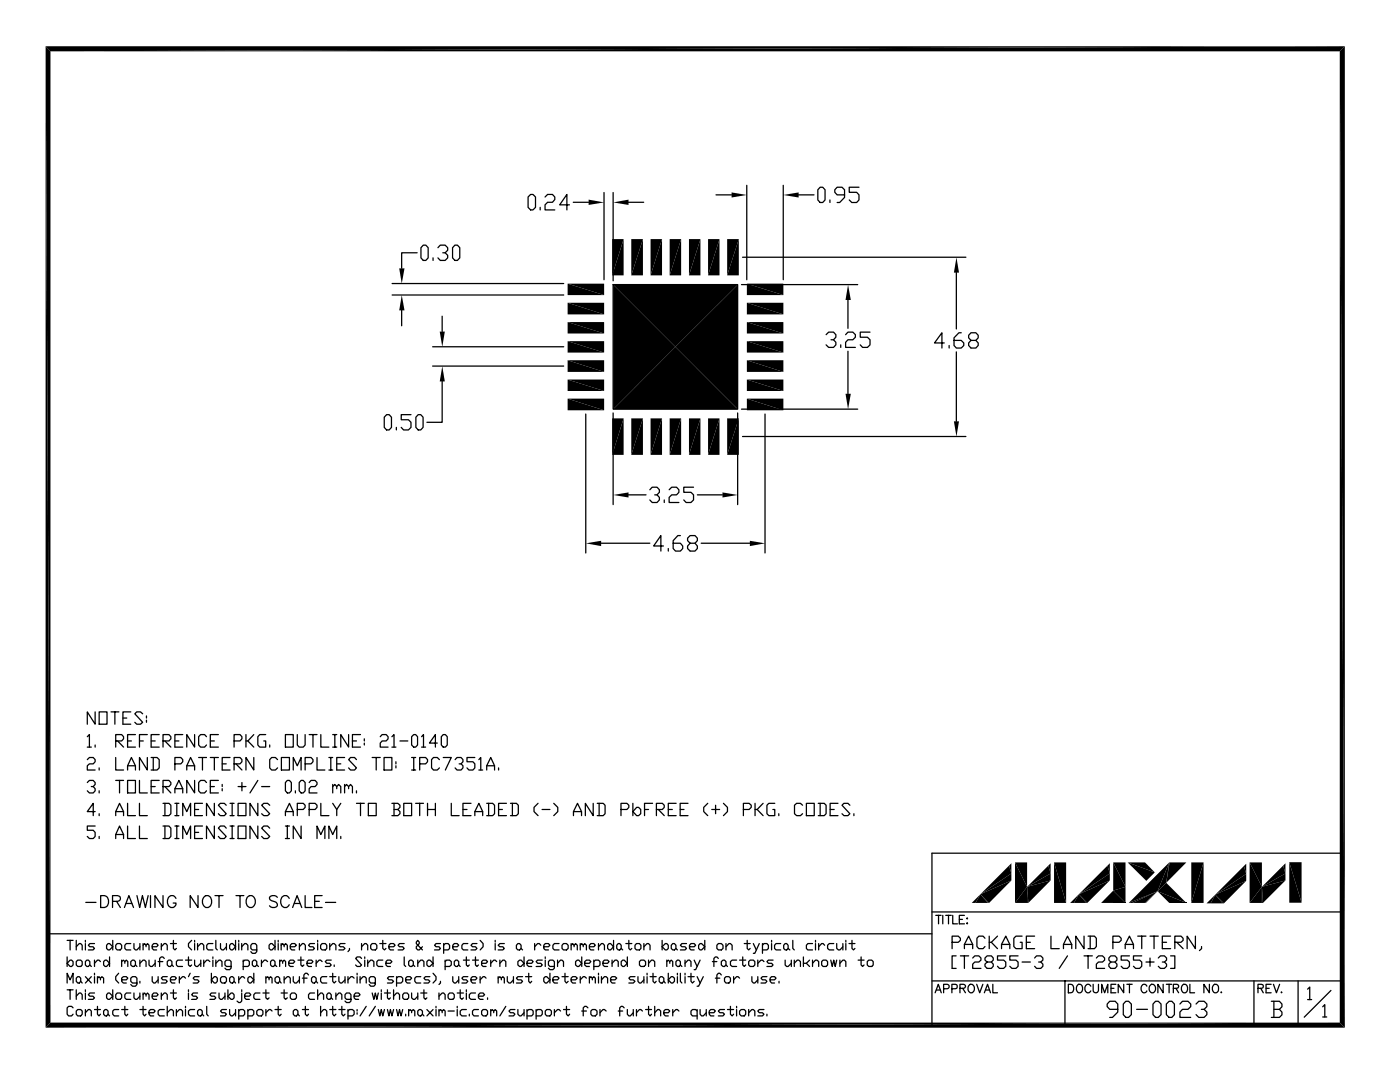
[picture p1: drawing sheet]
<svg xmlns="http://www.w3.org/2000/svg" width="279mm" height="216mm" viewBox="0 0 279 216" stroke-linecap="round" stroke-linejoin="round" font-family="sans-serif">
<g fill="none" stroke="#000" stroke-width=".25">
<path d="M105.4 39.3l.5-.5h.5l.5 .5v2.1l-.5 .5h-.5l-.5-.5zM108.8 39.3l.5-.5h1l.4 .5v.5l-.4 .6h-1l-.5 .5v1h1.9M120.5 38.4v17.4M122.4 38.4v17.6M142.9 38.9h3.1M149 37v18.8M156.3 37v18.8M159.4 38.9h3.1M163.7 37.4h.5l.5 .5v2l-.5 .5h-.5l-.5-.5v-2zM165.6 39.9v.5M168.6 38.9h-1.5l-.5-.5v-.5l.5-.5h.9l.6 .5v1.5l-1 1h-.5M171.4 37.4h-1.9v1h1.5l.4 .5v1l-.4 .5h-1l-.5-.5"/>
<path d="M78.3 56.6h34.2M78.3 58.9h34.2M83.2 50.4h-3v3.1M84.5 48.9h.5l.4 .5v2.1l-.4 .5h-.5l-.5-.5v-2.1zM86.4 51.5v.5M87.4 49.4l.5-.5h.9l.5 .5v.5l-.5 .5h-.4M88.8 50.4l.5 .5v.6l-.5 .5h-.9l-.5-.5M90.8 48.9h.5l.5 .5v2.1l-.5 .5h-.5l-.5-.5v-2.1zM107.8 41.4v.5M113.6 40.9h-1.9l1.4-2.1v3.1M114.4 40.4h3.1M122.4 56.8h24.8v24.8h-24.8z"/>
<path d="M125.4 40.4h3.1M148 56.8h23.2M148.2 51.3h44.6M169.2 59.8v5.7M190.9 54.4v11.2M80.2 61.9v3.1M86.3 73h26.2M86.3 69.2h26.2M88.2 76.1v8.2h-3M88.2 63.1v3M164.9 66.8l.5-.5h.9l.5 .5v.5l-.5 .5h-.5M166.3 67.8l.5 .5v.5l-.5 .5h-.9l-.5-.5"/>
<path d="M167.8 68.8v.5M168.8 66.8l.4-.5h1l.5 .5v.5l-.5 .5h-1l-.4 .5v1h1.9M169.2 70.1v8.4M173.6 66.3h-1.9v1h1.4l.5 .5v1l-.5 .5h-1l-.4-.5M188.4 68.4h-1.9l1.5-2v3M189.4 68.9v.5M190.9 70.2v13.9M191.8 66.4h-.4l-1 1v1.5l.5 .5h.9l.5-.5v-.5l-.5-.5h-1.4M193.8 67.9l-.5-.5v-.5l.5-.5h1l.4 .5v.5l-.4 .5h-1l-.5 .5v.5l.5 .5h1l.4-.5v-.5l-.4-.5M77.2 82.7h.5l.4 .5v2.1l-.4 .5h-.5l-.5-.5v-2.1zM79.1 85.3v.5M82 82.7h-1.9v1.1h1.4l.5 .5v1l-.5 .5h-1l-.4-.5"/>
<path d="M83.5 82.7h.5l.4 .5v2.1l-.4 .5h-.5l-.5-.5v-2.1zM116.9 82.6v27.7M122.4 82.4v18.3M125.4 98.7h3.5M129.7 97.7l.5-.5h.9l.5 .5v.5l-.5 .5h-.4M131.1 98.7l.5 .6v.5l-.5 .5h-.9l-.5-.5M132.6 99.8v.5M133.5 97.7l.5-.5h1l.5 .5v.5l-.5 .5h-1l-.5 .6v1h2M138.4 97.2h-1.9v1h1.4l.5 .5v1.1l-.5 .5h-1l-.4-.5M139.2 98.7h5M147.2 82.4v18.3M148 81.6h23.2"/>
<path d="M148.2 87.1h44.6M152.7 82.6v27.7M120 108.4h9.7M132.4 108.9h-1.9l1.4-2v3.1M133.4 109.5v.5M135.8 106.9h-.5l-1 1v1.6l.5 .5h1l.4-.5v-.6l-.4-.5h-1.5M137.7 108.4l-.5-.5v-.5l.5-.5h1l.5 .5v.5l-.5 .5h-1l-.5 .5v.6l.5 .5h1l.5-.5v-.6l-.5-.5M139.9 108.4h9.7M17.4 147l.4-.4v2.5M17.4 151.6l.4-.4h.8l.4 .4v.4l-.4 .4h-.8l-.4 .4v.8h1.6M17.4 156.1l.4-.4h.8l.4 .4v.4l-.4 .5h-.4M17.4 149.1h.8"/>
<path d="M18.6 157l.4 .4v.4l-.4 .4h-.8l-.4-.4M19 142v2.5l-1.6-2.5v2.5M19 148.7v.4M19.8 142h1.6v2.5h-1.6zM19.8 153.2v.4M19.8 157.8v.4M22.2 142h1.5M22.9 142v2.5M23.1 147.8h1.2l.4-.4v-.4l-.4-.4h-1.2v2.5M23.1 151.2v2.4h1.6M23.1 155.7h1.6M23.5 147.8l1.2 1.3"/>
<path d="M23.9 155.7v2.5M24.5 143.3h.8M25.5 153.6v-.8l.7-1.6 .8 1.6v.8M25.5 155.7h1.5v2.5h-1.5zM25.5 147.8h.7M25.5 152.8h1.5M26.1 142h-1.6v2.5h1.6M27 146.6h-1.5v2.5h1.5M27.8 155.7v2.5h1.6M27.8 147.8h.8M28.5 142.4l-.5-.4h-.7l-.4 .4 1.6 1.7-.5 .4h-.7l-.4-.4M29.2 142.9v.4"/>
<path d="M29.2 143.7v.4M29.4 146.6h-1.6v2.5M29.4 151.2v2.4l-1.6-2.4v2.4M30.2 151.2h1.1l.5 .4v1.6l-.5 .4h-1.1M30.2 147.8h.8M30.2 157h.8M30.6 151.2v2.4M31.8 146.6h-1.6v2.5h1.6M31.8 155.7h-1.6v2.5h1.6M32.5 147.8h1.2l.4-.4v-.4l-.4-.4h-1.2v2.5M32.5 157h1.2l.4-.5v-.4l-.4-.4h-1.2v2.5M32.9 147.8l1.2 1.3"/>
<path d="M32.9 157l1.2 1.2M34.9 152.4h1.2l.4-.4v-.4l-.4-.4h-1.2v2.4M34.9 158.2v-.8l.8-1.7 .8 1.7v.8M34.9 147.8h.8M34.9 157.4h1.6M36.5 146.6h-1.6v2.5h1.6M37.3 153.6v-.8l.7-1.6 .8 1.6v.8M37.3 152.8h1.5M38.8 146.6v2.5l-1.5-2.5v2.5M38.8 155.7v2.5l-1.5-2.5v2.5M39.6 151.2h1.6M40.4 151.2v2.4"/>
<path d="M41.2 147l-.4-.4h-.8l-.4 .4v1.7l.4 .4h.8l.4-.4M41.2 156.1l-.4-.4h-.8l-.4 .4v1.7l.4 .4h.8l.4-.4M42 147.8h.8M42 151.2h1.6M42 157h.8M42.8 151.2v2.4M43.6 146.6h-1.6v2.5h1.6M43.6 155.7h-1.6v2.5h1.6M44.3 152.4h.8M44.3 156.5v.5M44.3 157.4v.4M45.9 151.2h-1.6v2.4h1.6"/>
<path d="M46.7 147.8h1.2l.4-.4v-.4l-.4-.4h-1.2v2.5M46.7 152.4h1.2l.4-.4v-.4l-.4-.4h-1.2v2.4M47.1 152.4l1.2 1.2M47.5 157h1.6M48.3 156.1v1.7M49.1 146.6v2.5M49.5 147.8l1.2 1.3M50.7 146.6l-1.2 1.2h-.4M50.7 151.2v2.4l-1.6-2.4v2.4M51.5 155.7l-1.6 2.5M52.2 157h1.6M53 146.6h-1.2l-.3 .4v1.7l.3 .4h1.2v-1.3h-.4"/>
<path d="M53.8 148.7v.4M55.4 151.6l-.4-.4h-.8l-.4 .4v1.6l.4 .4h.8l.4-.4M56.2 151.2h1.6v2.4h-1.6zM57 146.6h1.5v2.5h-1.5zM57.3 155.7h.5l.3 .4v1.7l-.3 .4h-.5l-.3-.4v-1.7zM58.5 153.6v-2.4l.8 1.6 .8-1.6v2.4M58.9 157.8v.4M59.3 146.6v2.1l.4 .4h.8l.4-.4v-2.1M60.1 155.7h.4l.4 .4v1.7l-.4 .4h-.4l-.4-.4v-1.7zM60.9 152.4h1.2l.4-.4v-.4l-.4-.4h-1.2v2.4M61.7 156.1l.4-.4h.8l.4 .4v.4l-.4 .5h-.8l-.4 .4v.8h1.6M61.7 146.6h1.6"/>
<path d="M62.5 146.6v2.5M63.3 151.2v2.4h1.5M64 146.6v2.5h1.6M65.6 151.2h.8M65.6 153.6h.8M66 151.2v2.4M66.4 157l.4-.5 .4 .5v.4M66.4 149.1h.8M66.4 146.6h.8M66.4 156.5v1.7M66.8 146.6v2.5M67.2 157l.4-.5 .4 .5v1.2"/>
<path d="M67.2 152.4h.8M68.8 151.2h-1.6v2.4h1.6M68.8 157l.4-.5 .4 .5v.4M68.8 156.5v1.7M69.6 146.6v2.5l-1.6-2.5v2.5M69.6 157l.4-.5 .3 .5v1.2M70.3 147.8h.8M71.1 151.6l-.3-.4h-.8l-.4 .4 1.5 1.6-.3 .4h-.8l-.4-.4M71.1 157.8v.4M71.9 146.6h-1.6v2.5h1.6M72.7 147.4v.4M72.7 148.3v.4"/>
<path d="M74.3 151.2h1.6M75.1 151.2v2.4M75.9 147l.4-.4h.8l.3 .4v.4l-.3 .4h-.8l-.4 .5v.8h1.5M76.6 151.2h1.6v2.4h-1.6zM78.2 147l.4-.4v2.5M78.2 149.1h.8M79 152v.4M79 152.8v.4M79.8 147.8h1.6M82.1 147l.5-.4h.4l.3 .4v1.7l-.3 .4h-.4l-.5-.4zM82.1 151.2h.9M82.1 153.6h.9"/>
<path d="M82.6 151.2v2.4M83.8 152.4h1.1l.4-.4v-.4l-.4-.4h-1.1v2.4M84.1 147l.4-.4v2.5M84.1 149.1h.8M87.3 148.3h-1.6l1.2-1.7v2.5M87.7 151.6l-.4-.4h-.8l-.4 .4v1.6l.4 .4h.8l.4-.4M88.5 146.6h.4l.4 .4v1.7l-.4 .4h-.4l-.4-.4v-1.7zM88.5 151.2h1.6l-1.2 2.4M90.8 151.6l.4-.4h.8l.4 .4v.4l-.4 .4h-.4M92 152.4l.4 .4v.4l-.4 .4h-.8l-.4-.4M94.8 151.2h-1.6v.8h1.2l.4 .4v.8l-.4 .4h-.8l-.4-.4M95.6 151.6l.3-.4v2.4"/>
<path d="M95.6 153.6h.7M97.1 153.6v-.8l.8-1.6 .8 1.6v.8M97.1 152.8h1.6M99.5 153.2v.4M19 161.9h-1.6l1.2-1.6v2.5M19 164.8h-1.6v.9h1.2l.4 .4v.8l-.4 .4h-.8l-.4-.4M19.8 162.4v.4M19.8 166.9v.4M20.1 178.7a1.28 1.28 0 0 1 1.4 .5 1.28 1.28 0 0 1-.1 1.5l-.6 .4h-.7zM22.5 179.9l1.3-.2a.56 .56 0 0 0 0-.9l-1.3-.1v2.4M23.1 162.8v-.9l.8-1.6 .8 1.6v.9M23.1 167.3v-.8l.8-1.7 .8 1.7v.8"/>
<path d="M23.1 161.9h1.6M23.1 166.5h1.6M23.3 179.9l.7 1.2M25.5 160.3v2.5h1.5M25.5 164.8v2.5h1.5M27.3 178.7l.6 2.4 .5-2.4 .6 2.4 .6-2.4M27.8 160.3v2.5h1.6M27.8 164.8v2.5h1.6M30 178.7v2.4M32.5 160.3h1.2l.4 .4v1.7l-.4 .4h-1.2M32.5 164.8h1.2l.4 .4v1.7l-.4 .4h-1.2M32.5 178.7v2.4l-1.6-2.4v2.4"/>
<path d="M32.9 160.3v2.5M32.9 164.8v2.5M34.9 160.3h.8M34.9 162.8h.8M34.9 164.8h.8M34.9 167.3h.8M35.1 179.3a.87 .87 0 0 0-1-.6 .87 .87 0 0 0-.7 .9 1.09 1.09 0 0 0 1.2 1.5 .84 .84 0 0 0 .5-.9h-.5M35.3 160.3v2.5M35.3 164.8v2.5M36.5 162.8v-2.5l.8 1.6 .7-1.6v2.5M36.5 167.3v-2.5l.8 1.7 .7-1.7v2.5M38.8 161.5h.8"/>
<path d="M38.8 166.1h.8M39.5 178.7v2.4l-1.5-2.4v2.4M40.4 160.3h-1.6v2.5h1.6M40.4 164.8h-1.6v2.5h1.6M40.9 178.8a.91 .91 0 0 1 1.3 .8 1.09 1.09 0 0 1-1.1 1.5 1.35 1.35 0 0 1-.2-2.3zM42.8 160.3v2.5l-1.6-2.5v2.5M42.8 164.8v2.5l-1.6-2.5v2.5M42.9 178.7h1.6M43.7 178.7v2.4M45.1 160.7l-.3-.4h-.8l-.4 .4 1.5 1.7-.3 .4h-.8l-.4-.4M45.1 165.2l-.3-.4h-.8l-.4 .4 1.5 1.7-.3 .4h-.8l-.4-.4M45.9 160.3h.8"/>
<path d="M45.9 162.8h.8M45.9 164.8h.8M45.9 167.3h.8M46.3 160.3v2.5M46.3 164.8v2.5M47.1 178.7h1.6M47.5 160.3h1.6v2.5h-1.6zM47.5 164.8h1.6v2.5h-1.6zM47.9 178.7v2.4M49.3 179a.89 .89 0 0 1 1-.3 .89 .89 0 0 1 .6 .9 1.04 1.04 0 0 1-.2 1.1 1.04 1.04 0 0 1-1.1 .3 1.44 1.44 0 0 1-.3-2zM51.5 160.3v2.5l-1.6-2.5v2.5M51.5 164.8v2.5l-1.6-2.5v2.5"/>
<path d="M53.8 160.7l-.4-.4h-.8l-.4 .4 1.6 1.7-.4 .4h-.8l-.4-.4M53.8 165.2l-.4-.4h-.8l-.4 .4 1.6 1.7-.4 .4h-.8l-.4-.4M55.4 179a.88 .88 0 0 0-.9-.3 .88 .88 0 0 0-.7 .6l.2 .3 .9 .3a.61 .61 0 0 1 .2 1.1 1.05 1.05 0 0 1-1.3-.3M57 162.8v-.9l.8-1.6 .7 1.6v.9M57 161.9h1.5M57 164.8h.8M57 167.3h.8M57.3 164.8v2.5M57.7 179.3a.87 .87 0 0 0-1-.6 .87 .87 0 0 0-.7 .9 1.09 1.09 0 0 0 1.2 1.5l.5-.6M59.3 161.5h1.2l.4-.4v-.4l-.4-.4h-1.2v2.5M60.1 164.8v2.5l-1.6-2.5v2.5M60.9 178.7v2.4h1.4"/>
<path d="M61.7 161.5h1.2l.4-.4v-.4l-.4-.4h-1.2v2.5M62.8 179.9h.9M63.3 167.3v-2.5l.7 1.7 .8-1.7v2.5M64 160.3v2.5h1.6M64.3 178.7h-1.5v2.4h1.5M65.6 167.3v-2.5l.8 1.7 .8-1.7v2.5M66.4 160.3l.8 1.2v1.3M68 160.3l-.8 1.2M68 166.9v.4M71.1 160.3h1.6M71.9 160.3v2.5M73.5 160.3h1.6v2.5h-1.6z"/>
<path d="M78.2 160.3h1.2l.4 .4v.4l-.4 .4M78.6 161.5h.8l.4 .4v.5l-.4 .4h-1.2M78.6 160.3v2.5M80.6 160.3h1.5v2.5h-1.5zM83 160.3h1.5M83.8 160.3v2.5M85.3 161.5h1.6M85.3 160.3v2.5M86.9 160.3v2.5M90.1 160.3v2.5h1.5M92.4 161.5h.8M94 160.3h-1.6v2.5h1.6"/>
<path d="M94.8 162.8v-.9l.8-1.6 .7 1.6v.9M94.8 161.9h1.5M97.1 160.3h1.2l.4 .4v1.7l-.4 .4h-1.2M97.5 160.3v2.5M99.5 161.5h.8M101.1 160.3h-1.6v2.5h1.6M101.9 160.3h1.2l.3 .4v1.7l-.3 .4h-1.2M102.3 160.3v2.5M107.4 160.3l-.8 .8v.8l.8 .9M108.2 161.5h1.5M110.5 160.3l.8 .8v.8l-.8 .9M114.4 162.8v-.9l.9-1.6 .8 1.6v.9"/>
<path d="M114.4 161.9h1.7M118.4 160.3v2.5l-1.6-2.5v2.5M119.2 160.3h1.2l.4 .4v1.7l-.4 .4h-1.2M119.6 160.3v2.5M123.9 161.5h1.2l.4-.4v-.4l-.4-.4h-1.2v2.5M126.3 160.3v2.5M127.1 161.1h.3l.5 .4v.9l-.5 .4h-.3l-.8-.9zM128.6 161.5h.8M130.2 160.3h-1.6v2.5M131 161.5h1.2l.4-.4v-.4l-.4-.4h-1.2v2.5M131.4 161.5l1.2 1.3M133.4 161.5h.8"/>
<path d="M134.9 160.3h-1.5v2.5h1.5M135.7 161.5h.8M137.3 160.3h-1.6v2.5h1.6M141.2 160.3l-.8 .8v.8l.8 .9M142 161.5h1.6M142.8 160.7v1.7M144.4 160.3l.8 .8v.8l-.8 .9M148.4 161.5h1.1l.4-.4v-.4l-.4-.4h-1.1v2.5M150.7 160.3v2.5M151.1 161.5l1.2 1.3M152.3 160.3l-1.2 1.2h-.4M154.6 160.3h-1.2l-.3 .4v1.7l.3 .4h1.2v-1.3h-.4"/>
<path d="M155.4 162.4v.4M160.2 160.7l-.5-.4h-.7l-.4 .4v1.7l.4 .4h.7l.5-.4M160.9 160.3h1.6v2.5h-1.6zM163.3 160.3h1.2l.4 .4v1.7l-.4 .4h-1.2M163.7 160.3v2.5M165.7 161.5h.8M167.2 160.3h-1.5v2.5h1.5M169.6 160.7l-.4-.4h-.8l-.4 .4 1.6 1.7-.4 .4h-.8l-.4-.4M170.4 162.4v.4M205.1 177v3.2M267.9 170.2h-81.9v34.3M9.5 186.3h176.5"/>
<path d="M13.4 196.2v-2l.6 1.3 .6-1.3v2M13.4 197.5h1.2M13.4 187.6h1.2M13.4 190.9v1.9M14 191.6h.3l.3 .3v.7l-.3 .2h-.3l-.6-.6zM14 187.6v1.9M14 197.5v1.9M15.2 188.9l.6-.6h.3l.3 .3v.9M15.2 198.8l.6-.7h.3l.3 .4v.9M15.2 187.6v1.9M15.2 197.5v1.9M15.5 191.6h.6l.3 .3v.7l-.3 .2h-.6l-.3-.2v-.7z"/>
<path d="M15.5 194.9h.3l.3 .3v.6l-.3 .4h-.3l-.3-.4v-.6zM16.1 195.8l.3 .4M17 191.9l.3-.3h.3l.3 .3v.7l-.3 .2h-.3l-.3-.2zM17 187.6v.4M17 188.3v1.2M17 197.5v.3M17 198.1v1.3M17 194.9l1.2 1.3M17.1 180.1h2.1M17.9 192.6l.3 .2M18.2 194.9l-1.2 1.3M18.9 188.3h-1l-.3 .3 .3 .3h.7l.3 .4-.3 .2h-1"/>
<path d="M18.9 198.1h-1l-.3 .4 .3 .3h.7l.3 .3-.3 .3h-1M18.9 191.6v1.2M18.9 194.2v.3M18.9 194.9v1.3M19.5 195.2l.2-.3 .3 .3v.3M19.5 194.9v1.3M20 191.9l-.3-.3h-.2l-.6 .6M20 195.2l.3-.3 .4 .3v1M20.7 191.9l.3-.3h.3l.6 .6-.6 .6h-.3l-.3-.2zM21.6 188.3h.3l.6 .6-.6 .6h-.3l-.3-.2v-.7zM21.6 198.1h.3l.6 .7-.6 .6h-.3l-.3-.3v-.6zM21.9 190.9v1.9"/>
<path d="M22.5 187.6v1.9M22.5 197.5v1.9M23.4 188.3h.6l.3 .3v.7l-.3 .2h-.6l-.3-.2v-.7zM23.4 198.1h.6l.3 .4v.6l-.3 .3h-.6l-.3-.3v-.6zM23.7 194.2l-.6 .7v.6l.6 .7M24.3 191.9l.3-.3 .3 .3v.3M24.3 195.5h.9l.3-.3-.3-.3h-.6l-.3 .3v.6l.3 .4h.6M24.3 191.6v1.2M24.8 181.1l.9-2.4 .9 2.4M24.9 191.9l.3-.3 .3 .3v.9M25.2 180.3h1.1M26.1 188.3h-.9l-.3 .3v.7l.3 .2h.9"/>
<path d="M26.1 191.9l.3-.3h.3l.3 .3v.7l-.3 .2h-.3l-.3-.2zM26.1 198.1h-.9l-.3 .4v.6l.3 .3h.9M26.7 188.3v1l.3 .2h.3l.6-.6M26.7 198.1v1l.3 .3h.3l.6-.6M27 192.6l.3 .2M27.3 196.2h-.9l-.3-.4v-.6l.3-.3h.6l.3 .3v1.2l-.3 .4h-.6l-.3-.4M27.9 192.2l.7-.6h.3l.2 .3v.9M27.9 188.3v1.2M27.9 191.6v1.2M27.9 195.8v.4M27.9 198.1v1.3M28.6 188.6l.3-.3 .2 .3v.3"/>
<path d="M28.6 198.5l.3-.4 .2 .4v.3M28.6 188.3v1.2M28.6 198.1v1.3M29.1 188.6l.3-.3 .3 .3v.9M29.1 198.5l.3-.4 .3 .4v.9M29.7 191.6v1l.3 .2h.4l.6-.6M30.4 188.9h.9l.3-.3-.3-.3h-.6l-.3 .3v.7l.3 .2h.6M30.4 194.9v.9l.3 .4h.3l.6-.7M30.4 198.8h.9l.3-.3-.3-.4h-.6l-.3 .4v.6l.3 .3h.6M31 191.6v1.2M31.6 191.9h.9M31.6 194.9v1.3"/>
<path d="M32.2 188.9l.6-.6h.3l.3 .3v.9M32.2 198.8l.6-.7h.3l.3 .4v.9M32.2 188.3v1.2M32.2 198.1v1.3M32.8 191.2l-.3-.3h-.3l-.3 .3v1.6M33.4 191.9l.3-.3h.3l.3 .3v.7l-.3 .2h-.3l-.3-.2zM33.4 194.9h-.9l-.3 .3 .3 .3h.6l.3 .3-.3 .4h-.9M34 195.5h.9l.3-.3-.3-.3h-.6l-.3 .3v.6l.3 .4h.6M34 188.3h1.2M34 198.1h1.2M34.3 192.6l.3 .2M34.6 187.6v1.7l.3 .2 .3-.2"/>
<path d="M34.6 197.5v1.6l.3 .3 .3-.3M35.8 194.9v1.3M36.4 191.6h-.9l-.3 .3v.7l.3 .2h.9M37 195.2l-.3-.3h-.3l-.6 .6M37 191.6h1.2M37.6 190.9v1.7l.4 .2 .2-.2M37.6 197.5v.3M37.6 198.1v1.3M38 194.2l-.4 .7M38.2 187.6l-.6 .7v.6l.6 .6M38.8 191.6v1l.3 .2h.3l.7-.6M38.8 187.6v.4"/>
<path d="M38.8 188.3v1.2M39.4 188.9l.7-.6h.3l.3 .3v.9M39.4 198.1h-.9l-.3 .4 .3 .3h.6l.3 .3-.3 .3h-.9M39.4 188.3v1.2M39.7 194.9h-.9l-.3 .3 .3 .3h.6l.3 .3-.3 .4h-.9M40.1 191.6v1.2M40.7 191.6v1.2M41.9 191.9l-.3-.3h-.3l-.6 .6M42.2 194.2v2M42.5 188.3h-.9l-.3 .3v.7l.3 .2h.9M42.5 190.9v.3M42.5 191.6v1.2"/>
<path d="M42.8 194.9h.3l.3 .3v.6l-.3 .4h-.3l-.6-.7zM43.1 187.6v1.7l.3 .2M43.1 192.2l.6-.6h.3l.3 .3v.9M43.1 198.1h-.9l-.3 .4 .3 .3h.6l.3 .3-.3 .3h-.9M43.1 191.6v1.2M43.7 198.1v1l.3 .3h.3l.6-.6M44 188.3v1l.3 .2h.3l.6-.6M44 195.2l.3-.3h.6l.3 .3v.6l-.3 .4h-.6l-.3-.4zM44.9 198.1v1.3M45.2 188.3v1.2M45.5 197.5v1.9M46.1 188.3h.3l.6 .6-.6 .6h-.3l-.3-.2v-.7z"/>
<path d="M46.1 192.8h-.9l-.3-.2v-.7l.3-.3h.6l.3 .3v1.3l-.3 .3h-.6l-.3-.3M46.1 194.9h.3l.3 .3v.6l-.3 .4h-.3l-.3-.4v-.6zM46.1 198.1h.3l.3 .4v.6l-.3 .3h-.3l-.6-.6zM46.7 195.8l.3 .4M47 187.6v1.9M47.6 187.6v.4M47.6 188.3v1.2M47.6 194.9v1.3M48.2 188.9l.6-.6h.3l.4 .3v.9M48.2 198.1v1.6l-.3 .3h-.3l-.3-.3M48.2 188.3v1.2M48.2 197.5v.3"/>
<path d="M48.5 191.9l.3-.3h.7l.3 .3v.7l-.3 .2h-1M48.5 191.6v1.9M48.8 195.2l-.3-.3h-.3l-.6 .6M48.8 198.8h1l.3-.3-.3-.4h-.7l-.3 .4v.6l.3 .3h.7M49.8 194.9h.3l.6 .6-.6 .7h-.3l-.3-.4v-.6zM50.4 191.9l.3-.3h.2l.3 .3v.7l-.3 .2h-.2l-.3-.2zM50.7 194.2v2M51.2 189.5h-.8l-.3-.2v-.7l.3-.3h.5l.3 .3v1.3l-.3 .3h-.5l-.3-.3M51.2 192.6l.4 .2M51.9 198.1h-1l-.2 .4v.6l.2 .3h1M52.2 191.6v1.2M52.5 198.1h1.2"/>
<path d="M53.1 195.2l.3-.3 .3 .3v.3M53.1 197.5v1.6l.3 .3 .3-.3M53.1 194.9v1.3M53.4 191.9l-.3-.3h-.3l-.6 .6M53.7 195.2l.3-.3 .3 .3v1M54 188.3h.3l.6 .6-.6 .6h-.3l-.3-.2v-.7zM54 191.9l.3-.3h.3l.3 .3v.7l-.3 .2h-.3l-.3-.2zM54.9 195.2l.3-.3h.3l.3 .3v.6l-.3 .4h-.3l-.3-.4zM54.9 187.6v1.9M54.9 192.6l.3 .2M55.5 187.6v.4M55.5 188.3v1.2"/>
<path d="M55.8 191.9l.3-.3 .3 .3v.3M55.8 191.6v1.2M55.8 195.8l.3 .4M56.1 188.6l.3-.3 .3 .3v.3M56.1 188.3v1.2M56.1 198.1h1.2M56.4 191.9l.3-.3 .3 .3v.9M56.7 188.6l.3-.3 .3 .3v.9M56.7 195.5l.6-.6h.3l.3 .3v1M56.7 197.5v1.6l.3 .3 .3-.3M56.7 194.9v1.3M57.6 192.2h.9l.3-.3-.3-.3h-.6l-.3 .3v.7l.3 .2h.6"/>
<path d="M57.9 188.9h.9l.4-.3-.4-.3h-.6l-.3 .3v.7l.3 .2h.6M58.2 198.1h.6l.4 .4v.6l-.4 .3h-.6l-.3-.3v-.6zM58.4 181.1l.9-2.4 .9 2.4M58.5 194.9v.9l.3 .4h.4l.6-.7M58.7 180.3h1.2M59.5 191.6h1.1M59.8 188.9l.5-.6h.3l.3 .3v.9M59.8 188.3v1.2M59.8 194.9v1.3M60 190.9v1.7l.3 .2 .3-.2M60.3 195.2h1M61.3 192.2h.9l.3-.3-.3-.3h-.6l-.3 .3v.7l.3 .2h.6"/>
<path d="M61.6 194.5l-.3-.3h-.4l-.3 .3v1.7M62.5 194.9h.3l.3 .3v.6l-.3 .4h-.3l-.3-.4v-.6zM62.8 188.3h-.9l-.3 .3 .3 .3h.6l.3 .4-.3 .2h-.9M62.8 198.1h-.9l-.3 .4v.6l.3 .3h.9M63.1 191.6v1.2M63.1 195.8l.3 .4M63.4 198.8l.6-.7h.3l.3 .4v.9M63.4 187.6v.4M63.4 188.3v1.2M63.4 197.5v1.9M64.3 188.3h.6l.3 .3v.7l-.3 .2h-.6l-.3-.2v-.7zM64.3 191.9l-.3-.3h-.3l-.6 .6"/>
<path d="M65 180.1h2M65.2 194.9h-.9l-.3 .3v.6l.3 .4h.9M65.5 198.1h.3l.3 .4v.6l-.3 .3h-.3l-.3-.3v-.6zM65.8 188.9l.6-.6h.3l.3 .3v.9M65.8 188.3v1.2M65.8 194.9h1.2M66.1 191.6h-.9l-.3 .3 .3 .3h.6l.3 .4-.3 .2h-.9M66.1 199.1l.3 .3M66.4 194.2v1.6l.3 .4 .3-.4M66.7 192.6v.2M67 198.8l.6-.7h.3l.3 .4v.9M67 198.1v1.3"/>
<path d="M67.6 194.9v.9l.3 .4h.3l.7-.7M68.9 188.3h-1l-.3 .3 .3 .3h.6l.4 .4-.4 .2h-.9M68.9 194.9v1.3M69.4 194.9v1.3M69.7 189.3v.2l-.3 .4M70 199.4h-.8l-.3-.3v-.6l.3-.4h.5l.3 .4v1.2l-.3 .3h-.5l-.3-.3M70.7 195.2l-.4-.3h-.3l-.6 .6M70.7 198.8h.9l.3-.3-.3-.4h-.6l-.3 .4v.6l.3 .3h.6M71.3 194.2v.3M71.3 194.9v1.3M71.9 195.5l.6-.6h.3l.3 .3v1M71.9 194.9v1.3"/>
<path d="M72.2 188.9l.6-.6h.3l.3 .3v.9M72.2 191.2l-.3-.3h-.6l-.3 .3 1.2 1.4-.3 .2h-.6l-.3-.2M72.2 188.3v1.2M72.8 190.9v.3M72.8 191.6v1.2M73.4 192.2l.6-.6h.3l.3 .3v.9M73.4 191.6v1.2M74.3 188.3h.6l.3 .3v.7l-.3 .2h-.6l-.3-.2v-.7zM74.3 198.1l.3 1.3 .3-1.3 .3 1.3 .3-1.3M74.9 196.2h-.9l-.3-.4v-.6l.3-.3h.6l.3 .3v1.2l-.3 .4h-.6l-.3-.4M75.8 188.3h1.2M76.1 197.5v.3"/>
<path d="M76.1 198.1v1.3M76.4 187.6v1.7l.3 .2 .3-.2M76.4 191.6h-.9l-.3 .3v.7l.3 .2h.9M76.7 198.1h1.2M77 192.2h.9l.3-.3-.3-.3h-.6l-.3 .3v.7l.3 .2h.6M77.3 197.5v1.6l.3 .3 .3-.3M77.6 188.9h.9l.3-.3-.3-.3h-.6l-.3 .3v.7l.3 .2h.6M78.5 194.9h-.9l-.3 .3 .3 .3h.6l.3 .3-.3 .4h-.9M78.5 198.8l.6-.7h.3l.3 .4v.9M78.5 197.5v1.9M79.1 195.2l.3-.3h.6l.4 .3v.6l-.4 .4h-.9M79.1 194.9v1.9"/>
<path d="M80.7 188.3h-1l-.3 .3 .3 .3h.7l.3 .4-.3 .2h-1M80.7 190.9v1.7l.3 .2M80.7 198.1h.6l.3 .4v.6l-.3 .3h-.6l-.3-.3v-.6zM81 195.5h.9l.2-.3-.2-.3h-.6l-.3 .3v.6l.3 .4h.6M81.6 191.9l.3-.3h.2l.4 .3v.7l-.4 .2h-.2l-.3-.2zM82.1 198.1v1l.4 .3h.3l.6-.6M82.5 192.6l.3 .2M83.4 192.2l.6-.6h.3l.3 .3v.9M83.4 191.6v1.2M83.4 198.1v1.3M84 194.9h-.9l-.3 .3v.6l.3 .4h.9M84 198.1h1.2"/>
<path d="M84.3 188.9l-.6 .6h-.3l-.3-.2v-.4l.6-.6v-.3l-.3-.4-.3 .4v.3l1.2 1.2M84.6 197.5v1.6l.3 .3 .3-.3M85.2 191.9l.3-.3h.3l.6 .6-.6 .6h-.3l-.3-.2zM85.8 194.9h-.9l-.3 .3 .3 .3h.6l.3 .3-.3 .4h-.9M86.4 194.2l.6 .7v.6l-.6 .7M86.4 190.9v1.9M87.6 198.8l.6-.7h.3l.3 .4v.9M87.6 198.1v1.3M87.9 188.3h-.9l-.3 .3 .3 .3h.6l.3 .4-.3 .2h-.9M87.9 195.8v.4l-.3 .2M88.5 188.6l.3-.3h.6l.3 .3v.7l-.3 .2h-.9M88.5 188.3v1.9"/>
<path d="M88.8 191.9l.3-.3h.6l.4 .3v.7l-.4 .2h-.9M88.8 191.6v1.9M89.7 198.1h.7l.3 .4v.6l-.3 .3h-.7l-.3-.3v-.6zM90.4 188.9h.8l.3-.3-.3-.3h-.5l-.3 .3v.7l.3 .2h.5M90.4 194.9v.9l.3 .4h.3l.5-.7M90.7 191.9l.3-.3h.2l.3 .3v.7l-.3 .2h-.2l-.3-.2zM91.2 198.1h1.3M91.5 192.6l.3 .2M91.5 194.9v1.3M91.8 197.5v1.6l.4 .3 .3-.3M92.5 191.6h1.2M93.1 190.9v1.7l.3 .2 .3-.2"/>
<path d="M93.1 197.5v.3M93.1 198.1v1.3M93.4 188.3h-.9l-.3 .3v.7l.3 .2h.9M93.4 194.9h-.9l-.3 .3 .3 .3h.6l.3 .3-.3 .4h-.9M94 195.5h.9l.3-.3-.3-.3h-.6l-.3 .3v.6l.3 .4h.6M94.3 191.6h1.2M94.9 190.9v1.7l.3 .2 .3-.2M94.9 198.1h-.9l-.3 .4v.6l.3 .3h.9M95.2 188.3h-.9l-.3 .3 .3 .3h.6l.3 .4-.3 .2h-.9M95.5 198.8h.9l.3-.3-.3-.4h-.6l-.3 .4v.6l.3 .3h.6M95.8 187.6l.6 .7v.6l-.6 .6M95.8 194.9v1.3"/>
<path d="M96.1 192.2h.9l.3-.3-.3-.3h-.6l-.3 .3v.7l.3 .2h.6M97 195.2l-.3-.3h-.3l-.6 .6M97.3 199.1v.3M97.9 191.6v1.2M98.8 187.6v.4M98.8 188.3v1.2M99.1 191.9l-.3-.3h-.3l-.6 .6M99.4 195.2l.4-.3 .3 .3v.3M99.4 194.9v1.3M99.8 192.2l.6-.6h.2l.3 .3v.9M99.8 191.6v1.2M100.1 195.2l.3-.3 .2 .3v1"/>
<path d="M100.6 188.3h-.8l-.4 .3 .4 .3h.6l.2 .4-.2 .2h-1M101.2 194.9v.9l.4 .4h.3l.6-.7M102.5 194.9v1.3M103.4 188.3h.3l.3 .3v.7l-.3 .2h-.3l-.3-.2v-.7zM103.4 191.9l.3-.3h.3l.6 .6-.6 .6h-.3l-.3-.2zM104 189.3l.3 .2M104.3 194.9h-.9l-.3 .3 .3 .3h.6l.3 .3-.3 .4h-.9M104.6 190.9v1.9M104.9 194.9h1.2M105.2 192.2h.9l.3-.3-.3-.3h-.6l-.3 .3v.7l.3 .2h.6M105.5 194.2v1.6l.3 .4 .3-.4M106.7 188.3v1.2"/>
<path d="M107.9 188.6l-.3-.3h-.3l-.6 .6M108.2 191.6h-.9l-.3 .3 .3 .3h.6l.3 .4-.3 .2h-.9M108.5 188.9h1l.2-.3-.2-.3h-.7l-.3 .3v.7l.3 .2h.7M108.8 194.9h.3l.6 .6-.6 .7h-.3l-.3-.4v-.6zM108.8 190.9v.3M108.8 191.6v1.2M109.7 194.2v2M110.3 195.5h1l.3-.3-.3-.3h-.7l-.3 .3v.6l.3 .4h.7M110.6 192.8h-.9l-.2-.2v-.7l.2-.3h.6l.3 .3v1.3l-.3 .3h-.6l-.2-.3M111.3 192.2l.6-.6h.3l.3 .3v.9M111.3 191.6v1.2M111.6 188.3h-1l-.3 .3v.7l.3 .2h1"/>
<path d="M112.2 194.9h1.2M112.5 188.3h.6l.3 .3v.7l-.3 .2h-.6l-.3-.2v-.7zM112.8 194.2v1.6l.3 .4 .3-.4M114 188.6l.3-.3 .3 .3v.3M114 195.5h.9l.3-.3-.3-.3h-.6l-.3 .3v.6l.3 .4h.6M114 188.3v1.2M114.6 188.6l.3-.3 .3 .3v.9M114.9 191.9l.3-.3h.3l.6 .6-.6 .6h-.3l-.3-.2zM115.8 188.6l.3-.3 .3 .3v.3M115.8 188.3v1.2M115.8 194.9v1.3M116.1 190.9v1.9"/>
<path d="M116.4 188.6l.3-.3 .3 .3v.9M116.7 192.2h.9l.3-.3-.3-.3h-.6l-.3 .3v.7l.3 .2h.6M117 195.2l-.3-.3h-.3l-.6 .6M117.6 188.9h.9l.3-.3-.3-.3h-.6l-.3 .3v.7l.3 .2h.6M117.6 195.2l.3-.3 .3 .3v.3M117.6 194.9v1.3M118.2 195.2l.3-.3 .3 .3v1M118.5 191.9l.3-.3h.6l.3 .3v.7l-.3 .2h-.9M118.5 191.6v1.9M119.4 188.9l.6-.6h.3l.3 .3v.9M119.4 188.3v1.2M119.4 194.2v.3"/>
<path d="M119.4 194.9v1.3M120 195.5l.6-.6h.4l.3 .3v1M120 194.9v1.3M120.3 192.2h1l.3-.3-.3-.3h-.7l-.3 .3v.7l.3 .2h.7M121.6 188.3h.3l.5 .6-.5 .6h-.3l-.3-.2v-.7zM121.9 195.5h.8l.4-.3-.4-.3h-.5l-.3 .3v.6l.3 .4h.5M122.2 192.2l.5-.6h.4l.3 .3v.9M122.2 191.6v1.2M122.4 187.6v1.9M123.4 188.3h.3l.3 .3v.7l-.3 .2h-.3l-.3-.2v-.7zM124 191.9l.3-.3h.3l.6 .6-.6 .6h-.3l-.3-.2zM124 189.3l.3 .2"/>
<path d="M124.9 188.3h1.2M125.2 190.9v1.9M125.5 187.6v1.7l.3 .2 .3-.2M126.7 194.9h-.9l-.3 .3 .3 .3h.6l.3 .3-.3 .4h-.9M127 188.3h.6l.3 .3v.7l-.3 .2h-.6l-.3-.2v-.7zM127.3 194.9v.9l.3 .4h.3l.6-.7M127.6 191.9l.3-.3h.6l.3 .3v.7l-.3 .2h-.6l-.3-.2zM128.5 188.9l.6-.6h.3l.3 .3v.9M128.5 188.3v1.2M128.5 194.9v1.3M129.1 194.2v.3M129.1 194.9v1.3"/>
<path d="M129.4 192.2l.6-.6h.3l.4 .3v.9M129.4 191.6v1.2M129.7 194.9h1.3M130.3 194.2v1.6l.4 .4 .3-.4M131.8 194.9h.3l.4 .3v.6l-.4 .4h-.3l-.2-.4v-.6zM132.1 187.6v1.9M132.5 195.8l.3 .4M132.8 188.3h.3l.3 .3v.7l-.3 .2h-.3l-.7-.6zM133.1 191.9l.3-.3 .3 .3v.3M133.1 191.6v1.2M133.4 194.2v2M133.7 191.9l.3-.3 .3 .3v.9"/>
<path d="M134 194.9h.3l.3 .3v.6l-.3 .4h-.3l-.6-.7zM134.3 188.3h.3l.3 .3v.7l-.3 .2h-.3l-.3-.2v-.7zM134.9 191.9l.3-.3h.3l.3 .3v.7l-.3 .2h-.3l-.3-.2zM134.9 189.3l.3 .2M135.2 194.2v.3M135.2 194.9v1.3M135.8 194.2v1.6l.3 .4M135.8 192.6l.3 .2M136.7 192.2l.6-.6h.3l.3 .3v.9M136.7 191.6v1.2M136.7 194.2v.3M136.7 194.9v1.3"/>
<path d="M137 188.3h-.9l-.3 .3 .3 .3h.6l.3 .4-.3 .2h-.9M137.3 194.9h1.2M137.6 188.9h.9l.3-.3-.3-.3h-.6l-.3 .3v.7l.3 .2h.6M137.9 194.2v1.6l.3 .4 .3-.4M138.5 191.6l.6 1.2M139.1 194.9l.6 1.3M139.7 188.3h.3l.7 .6-.7 .6h-.3l-.3-.2v-.7zM139.7 191.6l-.9 1.9h-.3M140.4 194.9l-1 1.9h-.3M140.7 187.6v1.9M142.2 191.9h.9M142.8 195.2h.9"/>
<path d="M143.4 188.3h.6l.3 .3v.7l-.3 .2h-.6l-.3-.2v-.7zM143.4 191.2l-.3-.3h-.3l-.3 .3v1.6M144 191.9l.3-.3h.3l.3 .3v.7l-.3 .2h-.3l-.3-.2zM144 194.5l-.3-.3h-.3l-.3 .3v1.7M144.9 188.9l.6-.6h.3l.3 .3v.9M144.9 194.9h.6l.3 .3v.6l-.3 .4h-.6l-.3-.4v-.6zM144.9 188.3v1.2M144.9 192.6l.3 .2M146.4 194.9v1.3M147 191.6h-.9l-.3 .3v.7l.3 .2h.9M147.6 195.2l-.3-.3h-.3l-.6 .6M147.6 191.6h1.2"/>
<path d="M148.2 190.9v1.7l.3 .2 .3-.2M148.5 188.3h1.2M149.1 187.6v1.7l.3 .2 .3-.2M149.4 191.9l.3-.3h.6l.3 .3v.7l-.3 .2h-.6l-.3-.2zM150.1 194.9v.9l.2 .4h.3l.6-.7M150.3 188.3l.6 1.2M151.2 191.6v1.2M151.2 194.9v1.3M151.5 188.3l-.9 1.9h-.3M152.2 188.6l.3-.3h.6l.3 .3v.7l-.3 .2h-.9M152.2 188.3v1.9M152.5 191.9l-.3-.3h-.3l-.7 .6"/>
<path d="M153.1 194.9h-.9l-.3 .3 .3 .3h.6l.3 .3-.3 .4h-.9M153.7 195.5h.9l.3-.3-.3-.3h-.6l-.3 .3v.6l.3 .4h.6M154 187.6v.4M154 188.3v1.2M154.3 191.6h-.9l-.3 .3 .3 .3h.6l.3 .4-.3 .2h-.9M155.5 195.8v.4M155.8 188.3h-.9l-.3 .3v.7l.3 .2h.9M156.7 188.3h.3l.3 .3v.7l-.3 .2h-.3l-.3-.2v-.7zM156.7 191.6v1l.3 .2h.3l.6-.6M157.3 189.3l.3 .2M157.9 191.6v1.2M158.2 187.6v1.7l.3 .2"/>
<path d="M158.5 192.2l.6-.6h.3l.3 .3v.9M158.5 191.6v1.2M160.3 190.9v1.9M160.9 192.2l.7 .6M161.6 191.6l-.7 .6h-.6M162.2 188.3h-1l-.3 .3v.7l.3 .2h1M162.2 192.2l.6-.6h.2l.4 .3v.9M162.2 191.6v1.2M162.8 187.6v.4M162.8 188.3v1.2M163.4 188.3v1.2M164 191.9l.3-.3h.6l.3 .3v.7l-.3 .2h-.6l-.3-.2z"/>
<path d="M164.6 188.6l-.3-.3h-.3l-.6 .6M165.8 191.6l.3 1.2 .3-1.2 .3 1.2 .3-1.2M166.4 188.3h-.9l-.3 .3v.7l.3 .2h.9M167 188.3v1l.3 .2h.3l.6-.6M167.6 192.2l.6-.6h.3l.3 .3v.9M167.6 191.6v1.2M168.2 188.3v1.2M168.8 187.6v.4M168.8 188.3v1.2M169.4 188.3h1.2M170 187.6v1.7l.3 .2 .3-.2M171.3 191.6h1.1"/>
<path d="M171.9 190.9v1.7l.2 .2 .3-.2M173.1 191.9l.3-.3h.6l.3 .3v.7l-.3 .2h-.6l-.3-.2zM186 195.7h81.9M186 182h81.9M186.6 198.1l.7-1.7 .6 1.7M186.8 182.6h1M186.9 197.5h.7M187.3 182.6v1.7M188.2 182.6v1.7M188.3 197.3h.7a.45 .45 0 0 0 .4-.5 .45 .45 0 0 0-.4-.4h-.7v1.7M188.7 182.6h1.1M189.3 182.6v1.7"/>
<path d="M190 197.3l.9-.1 .1-.6-.4-.2h-.6v1.7M190 188h1.2l.5-.4v-.4l-.5-.4h-1.2v2.5M190.1 182.6v1.7h1M190.8 190.7h-.8v2.5h.8M191.5 183.5h.6M191.6 197.2l.9-.1 .2-.4-.4-.3h-.7v1.7M191.7 190.7h1.6M192.1 197.2l.6 .9M192.5 182.6h-1v1.7h1M192.5 189.3v-.9l.8-1.6 .8 1.6v.9M192.5 188.4h1.6M192.5 190.7v2.5"/>
<path d="M193 183.2v.2zM193 184.2v.1zM193.5 196.5a.8 .8 0 0 1 1 .4 .8 .8 0 0 1-.2 .9l-.2 .2a.8 .8 0 0 1-.9-.4 .8 .8 0 0 1 .2-.9zM194.1 191.2l.4-.5h.8l.5 .5v.4l-.5 .4h-.8l-.4 .4v.8h1.7M194.9 196.4l.6 1.7 .7-1.7M196.4 198.1l.7-1.7 .6 1.7M196.6 187.2l-.4-.4h-.9l-.3 .4v1.7l.3 .4h.9l.4-.4M196.7 197.5h.8M197 192l-.4-.4v-.4l.4-.5h.8l.4 .5v.4l-.4 .4h-.8l-.4 .4v.4l.4 .4h.8l.4-.4v-.4l-.4-.4M197.4 186.8v2.5M197.8 188l1.3 1.3M198.1 196.4v1.7h1"/>
<path d="M199.1 186.8l-1.3 1.2h-.4M199.9 189.3v-.9l.8-1.6 .8 1.6v.9M199.9 188.4h1.6M200.7 190.7h-1.6v.9h1.2l.4 .4v.8l-.4 .4h-.8l-.4-.4M203.2 190.7h-1.7v.9h1.3l.4 .4v.8l-.4 .4h-.8l-.5-.4M204 186.8h-1.2l-.5 .4v1.7l.5 .4h1.2v-1.3h-.4M204 192h1.6M204.8 188h.8M206.5 186.8h-1.7v2.5h1.7M206.5 191.2l.4-.5h.8l.4 .5v.4l-.4 .4h-.4M207.7 192l.4 .4v.4l-.4 .4h-.8l-.4-.4M209.7 186.8v2.5h1.7"/>
<path d="M212.2 189.3v-.9l.8-1.6 .9 1.6v.9M212.2 188.4h1.7M212.5 195.7v8.8M213 190.7l-1.6 2.5M213.2 196.4a.87 .87 0 0 1 1.1 .9 .87 .87 0 0 1-1.1 .8zM215.1 196.5a.56 .56 0 0 1 .8 .2 .85 .85 0 0 1 .2 .9 .85 .85 0 0 1-.8 .5 1.01 1.01 0 0 1-.2-1.6zM216.3 186.8v2.5l-1.6-2.5v2.5M216.3 190.7h1.7M217.1 186.8h1.3l.4 .4v1.7l-.4 .4h-1.3M217.1 190.7v2.5M217.6 186.8v2.5M217.7 196.8a.61 .61 0 0 0-.7-.4 .61 .61 0 0 0-.5 .6 .74 .74 0 0 0 .2 .8 .74 .74 0 0 0 .7 .2l.3-.3"/>
<path d="M218.2 196.4v1.2a.53 .53 0 0 0 .5 .5 .53 .53 0 0 0 .5-.5v-1.2M218.8 191.2l.4-.5h.8l.5 .5v.4l-.5 .4h-.8l-.4 .4v.8h1.7M219.9 198.1v-1.7l.6 1.7 .6-1.7v1.7M221.7 192l-.4-.4v-.4l.4-.5h.8l.4 .5v.4l-.4 .4h-.8l-.4 .4v.4l.4 .4h.8l.4-.4v-.4l-.4-.4M221.7 197.2h.6M222.1 188h1.2l.5-.4v-.4l-.5-.4h-1.2v2.5M222.7 196.4h-1v1.7h1M224.3 196.4v1.7l-1.1-1.7v1.7M224.6 189.3v-.9l.8-1.6 .8 1.6v.9M224.6 188.4h1.6M224.7 199.8h.5l.6 .5v2.2l-.6 .5h-.5l-.5-.5v-2.2zM224.9 196.4h1.1"/>
<path d="M225.4 190.7h-1.6v.9h1.2l.4 .4v.8l-.4 .4h-.8l-.4-.4M225.4 196.4v1.7M227.1 186.8h1.6M227.9 190.7h-1.7v.9h1.2l.5 .4v.8l-.5 .4h-.8l-.4-.4M227.9 186.8v2.5M228.7 192h1.6M228.9 196.8a.59 .59 0 0 0-.7-.4 .59 .59 0 0 0-.5 .6v.5a.59 .59 0 0 0 .5 .6 .59 .59 0 0 0 .7-.4M229.5 186.8h1.7M229.5 191.2v1.6M229.7 196.5a.8 .8 0 0 1 .9 .4 .8 .8 0 0 1-.2 .9l-.1 .2a.8 .8 0 0 1-1-.4 .8 .8 0 0 1 .2-.9zM230.3 186.8v2.5M230.6 199.8h.6l.5 .5v2.2l-.5 .5h-.6l-.5-.5v-2.2z"/>
<path d="M231.2 191.2l.4-.5h.8l.4 .5v.4l-.4 .4h-.4M232 188h.8M232.1 196.4v1.7l-1-1.7v1.7M232.4 192l.4 .4v.4l-.4 .4h-.8l-.4-.4M232.8 196.4h1M233.3 196.4v1.7M233.6 186.8h-1.6v2.5h1.6M233.6 190.7h.9v2.5h-.9M234.2 197.2l.9-.1 .1-.2-.1-.4-.9-.1v1.7M234.5 188h1.2l.4-.4v-.4l-.4-.4h-1.2v2.5M234.7 197.2l.5 .9M234.8 188l1.3 1.3"/>
<path d="M236.1 196.5a.56 .56 0 0 1 .8 .2 .85 .85 0 0 1 .1 .9 .85 .85 0 0 1-.8 .5 1.01 1.01 0 0 1-.1-1.6zM237.5 196.4v1.7h.9M238.6 186.8v2.5l-1.7-2.5v2.5M239.8 188.9v.4l-.4 .4M241.4 196.4v1.7l-1.1-1.7v1.7M242.3 196.5a.61 .61 0 0 1 .9 .5 .76 .76 0 0 1-.8 1.1 1.01 1.01 0 0 1-.1-1.6zM243.7 197.9l-.1 .1h.2M250.3 195.7v8.8M251.1 197.2l.9-.1 .1-.5-.4-.2h-.6v1.7M251.6 197.2l.5 .9M252.7 197.2h.6M253.7 196.4h-1v1.7h1"/>
<path d="M253.7 199.8h1.6l.5 .5v.6l-.5 .5M254.1 196.4l.6 1.7 .7-1.7M254.2 199.8v3.2M255.8 197.9l-.1 .1h.1M259.1 195.7v8.8M261 197.4l.4-.4v2.5M261 199.5h.8M265.6 197.6l-5.3 5.4M14.6 201.1l-.3-.3h-.6l-.3 .3v1.3l.3 .3h.6l.3-.3M15.5 201.4h.6l.3 .3v.7l-.3 .3h-.6l-.3-.3v-.7zM17 202.1l.6-.7h.3l.3 .3v1M17 201.4v1.3"/>
<path d="M18.9 201.4h1.1M19.5 200.8v1.6l.2 .3 .3-.3M20.7 201.7l.3-.3h.3l.3 .3v.7l-.3 .3h-.3l-.3-.3zM21.6 202.4l.3 .3M23.7 201.4h-.9l-.3 .3v.7l.3 .3h.9M24.3 201.4h1.2M24.9 200.8v1.6l.3 .3 .3-.3M27.9 201.4h1.2M28.6 200.8v1.6l.3 .3 .2-.3M29.7 202.1h1l.3-.4-.3-.3h-.7l-.3 .3v.7l.3 .3h.7M32.8 201.4h-.9l-.3 .3v.7l.3 .3h.9M33.4 202.1l.6-.7h.3l.3 .3v1"/>
<path d="M33.4 200.8v1.9M35.2 202.1l.6-.7h.3l.3 .3v1M35.2 201.4v1.3M37 200.8v.3M37 201.4v1.3M38.8 201.4h-.8l-.4 .3v.7l.4 .3h.8M39.7 201.4h.4l.3 .3v.7l-.3 .3h-.4l-.3-.3v-.7zM40.4 202.4l.3 .3M41.3 200.8v1.6l.3 .3M45.2 201.4h-.9l-.3 .3 .3 .4h.6l.3 .3-.3 .3h-.9M45.8 201.4v1l.3 .3h.3l.6-.6M47 201.4v1.3"/>
<path d="M47.6 201.7l.3-.3h.6l.3 .3v.7l-.3 .3h-.9M47.6 201.4v1.9M49.5 201.7l.3-.3h.6l.3 .3v.7l-.3 .3h-.9M49.5 201.4v1.9M51.2 201.7l.4-.3h.6l.3 .3v.7l-.3 .3h-.6l-.4-.3zM53.1 201.4v1.3M54.3 201.7l-.3-.3h-.3l-.6 .7M54.9 201.4h1.2M55.5 200.8v1.6l.3 .3 .3-.3M58.8 201.4h.4l.3 .3v.7l-.3 .3h-.4l-.3-.3v-.7zM59.5 202.4l.3 .3M60.3 201.4h1.3"/>
<path d="M60.9 200.8v1.6l.4 .3 .3-.3M64 202.1l.6-.7h.3l.3 .3v1M64 200.8v1.9M65.8 201.4h1.2M66.4 200.8v1.6l.3 .3 .3-.3M67.6 201.4h1.3M68.2 200.8v1.6l.3 .3 .4-.3M69.4 201.7l.3-.3h.6l.4 .3v.7l-.4 .3h-.9M69.4 201.4v1.9M71.3 201.4v.3M71.3 202.1v.3M73.1 200.8l-1.2 1.9"/>
<path d="M74.9 200.8l-1.2 1.9M75.5 201.4l.3 1.3 .3-1.3 .3 1.3 .3-1.3M77.3 201.4l.3 1.3 .3-1.3 .3 1.3 .3-1.3M79.1 201.4l.3 1.3 .3-1.3 .3 1.3 .4-1.3M81 202.4v.3M81.6 201.7l.3-.3 .2 .3v.4M81.6 201.4v1.3M82.1 201.7l.4-.3 .3 .3v1M83.7 201.4h.3l.3 .3v.7l-.3 .3h-.3l-.3-.3v-.7zM84.3 202.4l.3 .3M85.2 201.4l1.2 1.3M86.4 201.4l-1.2 1.3"/>
<path d="M87 200.8v.3M87 201.4v1.3M87.6 201.7l.3-.3 .3 .3v.4M87.6 201.4v1.3M88.2 201.7l.3-.3 .3 .3v1M89.4 201.7h1.3M91.2 200.8v.3M91.2 201.4v1.3M93.1 201.4h-.9l-.4 .3v.7l.4 .3h.9M93.7 202.4v.3M95.5 201.4h-.9l-.3 .3v.7l.3 .3h.9M96.4 201.4h.6l.3 .3v.7l-.3 .3h-.6l-.3-.3v-.7z"/>
<path d="M97.9 201.7l.3-.3 .3 .3v.4M97.9 201.4v1.3M98.5 201.7l.3-.3 .3 .3v1M100.9 200.8l-1.1 1.9M102.8 201.4h-.9l-.3 .3 .3 .4h.6l.3 .3-.3 .3h-.9M103.4 201.4v1l.3 .3h.3l.6-.6M104.6 201.4v1.3M105.2 201.7l.3-.3h.6l.3 .3v.7l-.3 .3h-.9M105.2 201.4v1.9M107 201.7l.3-.3h.6l.3 .3v.7l-.3 .3h-.9M107 201.4v1.9M109.1 201.4h.6l.3 .3v.7l-.3 .3h-.6l-.3-.3v-.7z"/>
<path d="M110.6 201.4v1.3M111.9 201.7l-.3-.3h-.3l-.7 .7M112.5 201.4h1.2M113.1 200.8v1.6l.3 .3 .3-.3M116.1 201.7h.9M117.3 201.1l-.3-.3h-.3l-.3 .3v1.6M118.2 201.4h.6l.3 .3v.7l-.3 .3h-.6l-.3-.3v-.7zM119.7 201.4v1.3M121 201.7l-.4-.3h-.3l-.6 .7M123.4 201.7h.9M124.6 201.1l-.3-.3h-.3l-.3 .3v1.6M125.2 201.4v1l.3 .3h.3l.6-.6"/>
<path d="M126.4 201.4v1.3M127 201.4v1.3M128.2 201.7l-.3-.3h-.3l-.6 .7M128.8 201.4h1.2M129.4 200.8v1.6l.3 .3 .3-.3M130.7 202.1l.6-.7h.3l.2 .3v1M130.7 200.8v1.9M132.5 202.1h.9l.3-.4-.3-.3h-.6l-.3 .3v.7l.3 .3h.6M134.3 201.4v1.3M135.5 201.7l-.3-.3h-.3l-.6 .7M139.1 201.7l-.3-.3h-.6l-.3 .3v.7l.3 .3h.9M139.1 201.4v1.9"/>
<path d="M139.7 201.4v1l.3 .3h.4l.5-.6M140.9 201.4v1.3M141.5 202.1h1l.3-.4-.3-.3h-.7l-.3 .3v.7l.3 .3h.7M144.6 201.4h-.9l-.3 .3 .3 .4h.6l.3 .3-.3 .3h-.9M145.2 201.4h1.2M145.8 200.8v1.6l.3 .3 .3-.3M147 200.8v.3M147 201.4v1.3M147.6 201.7l.3-.3h.6l.3 .3v.7l-.3 .3h-.6l-.3-.3zM149.4 202.1l.7-.7h.2l.3 .3v1M149.4 201.4v1.3M152.5 201.4h-1l-.3 .3 .3 .4h.7l.3 .3-.3 .3h-1"/>
<path d="M153.1 202.4v.3M223.1 201.4h-1.6l-.5-.5v-.6l.5-.5h1.1l.5 .5v1.7l-1.1 1h-.5M226.8 201.4h2.2M232.8 200.3l.5-.5h.6l.5 .5v2.2l-.5 .5h-.6l-.5-.5zM235.5 200.3l.5-.5h1.1l.5 .5v.6l-.5 .5h-1.1l-.5 .6v1h2.1M238.7 200.3l.5-.5h1.1l.6 .5v.6l-.6 .5h-.5M240.3 201.4l.6 .6v.5l-.6 .5h-1.1l-.5-.5M254.2 201.4h1.1l.5 .6v.5l-.5 .5h-1.6M264 200.9l.4-.4v2.4M264 202.9h.8"/>
</g>
<g fill="#000">
<path d="M9.1 9.2l1 194.8-1 1.1zM9.1 9.2l1 1v193.8zM10.1 10.2l258.3-1-1 1zM9.1 9.2h259.3l-258.3 1zM117.5 39.8l3.1 .6-3.1 .5zM122.4 40.4l3-.6v1.1zM146 38.4l3.1 .5-3.1 .5zM156.3 38.9l3.1-.5v1zM79.7 53.6h1l-.5 3zM113.3 56.6l7.3 2.3h-7.3zM113.3 56.6h7.3v2.3zM122.2 47.7h2.3l-2.3 7.2z"/>
<path d="M124.5 47.7v7.2h-2.3zM126 47.7h2.3l-2.3 7.2zM128.3 47.7v7.2h-2.3zM129.8 47.7h2.3l-2.3 7.2zM132.1 47.7v7.2h-2.3zM133.6 47.7h2.3l-2.3 7.2zM135.9 47.7v7.2h-2.3zM137.5 47.7h2.3l-2.3 7.2zM139.8 47.7v7.2h-2.3zM141.3 47.7h2.3l-2.3 7.2zM143.6 47.7v7.2h-2.3zM145.1 47.7h2.3l-2.3 7.2z"/>
<path d="M147.4 47.7v7.2h-2.3zM149.1 56.6l7.2 2.3h-7.2zM149.1 56.6h7.2v2.3zM169.2 56.8l.6 3.1h-1.1zM190.9 51.4l.5 3h-1zM80.2 58.9l.5 3h-1zM87.8 66.2h1l-.5 3zM88.3 73.1l.5 3h-1zM113.3 60.4l7.3 2.3h-7.3zM113.3 60.4h7.3v2.3zM113.3 64.3l7.3 2.2h-7.3zM113.3 64.3h7.3v2.2z"/>
<path d="M113.3 68.1l7.3 2.3h-7.3zM113.3 68.1h7.3v2.3zM113.3 71.9l7.3 2.3h-7.3zM113.3 71.9h7.3v2.3zM113.3 75.7l7.3 2.3h-7.3zM113.3 75.7h7.3v2.3zM113.3 79.5l7.3 2.4h-7.3zM113.3 79.5h7.3v2.4zM122.4 56.8h24.8l-12.4 12.4zM122.4 56.8l12.4 12.4-12.4 12.5zM134.8 69.2l12.4 12.5h-24.8zM134.8 69.2l12.4-12.4v24.9z"/>
<path d="M149.1 79.5l7.2 2.4h-7.2zM149.1 79.5h7.2v2.4zM149.1 75.7l7.2 2.3h-7.2zM149.1 75.7h7.2v2.3zM149.1 71.9l7.2 2.3h-7.2zM149.1 71.9h7.2v2.3zM149.1 68.1l7.2 2.3h-7.2zM149.1 68.1h7.2v2.3zM149.1 64.3l7.2 2.2h-7.2zM149.1 64.3h7.2v2.2zM149.1 60.4l7.2 2.3h-7.2zM149.1 60.4h7.2v2.3z"/>
<path d="M168.7 78.6h1.1l-.6 3.1zM122.2 83.5h2.3l-2.3 7.3zM124.5 83.5v7.3h-2.3zM122.4 98.8l3-.5v1zM126 83.5h2.3l-2.3 7.3zM128.3 83.5v7.3h-2.3zM129.8 83.5h2.3l-2.3 7.3zM132.1 83.5v7.3h-2.3zM133.6 83.5h2.3l-2.3 7.3zM135.9 83.5v7.3h-2.3zM137.5 83.5h2.3l-2.3 7.3zM139.8 83.5v7.3h-2.3z"/>
<path d="M141.3 83.5h2.3l-2.3 7.3zM143.6 83.5v7.3h-2.3zM144.2 98.3l3 .5-3 .5zM145.1 83.5h2.3l-2.3 7.3zM147.4 83.5v7.3h-2.3zM190.4 84.1h1l-.5 3zM116.9 108.4l3.1-.5v1.1zM149.6 107.9l3.1 .5-3.1 .6zM195.7 178.4l1.7 1.8h-.3zM195.7 178.4l1.4 1.8h-2.4zM193.9 180.2l1.8-1.8-1 1.8zM201.4 172.7l.4 1.6-6.1 4.1z"/>
<path d="M195.7 178.4l6.1-2.7-4.4 4.5zM195.7 178.4l6.1-4.1v1.4zM201.4 172.7l.4-.4v2zM202.6 172.1l2.4 4.9-2.4 3.2zM205 177v3.2h-2.4zM202.6 172.1h2.4v4.9zM205 177l4.2-4.3 .5 1.6zM205 177l4.7-1.3-4.5 4.5zM205 177l4.7-2.7v1.4zM209.2 172.7l.5-.4v2zM210.4 172.1l2.4 8.1h-2.4zM215.3 178.4l1.7 1.8h-.2z"/>
<path d="M215.3 178.4l1.5 1.8h-2.5zM213.6 180.2l1.7-1.8-1 1.8zM221 172.7l.5 1.6-6.2 4.1zM215.3 178.4l6.2-2.7-4.5 4.5zM215.3 178.4l6.2-4.1v1.4zM221.5 172.3v2l-.5-1.6zM222.2 177.7l2.4 2.5h-4.8zM222.2 172.1l2.4 4.9-2.4 .7zM222.2 177.7l2.4-.7v3.2zM222.2 172.1h2.4v4.9zM225 172.1l5.5 2-1.7 1.7zM225 172.1h3.5l2 2z"/>
<path d="M228.5 180.2l2.5-2.4-2.3 2.4zM226 180.2l5-2.4-2.5 2.4zM225.3 180.2l5.7-2.4-5 2.4zM231 177.8l5.8 2.4h-3.5zM231 177.8l1.7-1.7 4.1 4.1zM233.4 172.1h3.4l-4.1 4zM233.3 172.1l-.6 4zM233.3 172.1l-.6 4-1.7 1.7zM225.3 180.2l8-8.1-2.3 5.7zM237.7 172.1h2.5l-2.5 8.1zM240.2 172.1v8.1h-2.5zM242.5 178.5l1.8 1.8h-.3z"/>
<path d="M242.5 178.5l1.5 1.8h-2.4zM240.8 180.3l1.7-1.8-.9 1.8zM248.2 172.8l.5 1.6-6.2 4.1zM242.5 178.5l6.2-2.7-4.4 4.5zM242.5 178.5l6.2-4.1v1.4zM248.2 172.8l.5-.5v2.1zM249.4 172.1l2.4 4.9-2.4 3.2zM251.8 177v3.2h-2.4zM249.4 172.1h2.4v4.9zM251.8 177l4.3-4.3 .4 1.6zM251.8 177l4.7-1.3-4.4 4.5zM251.8 177l4.7-2.7v1.4z"/>
<path d="M256.1 172.7l.4-.4v2zM257.3 172l2.5 8.1h-2.5zM210.4 172.1h2.4v8.1zM257.3 172h2.5v8.1zM9.1 205.1l258.3-1.1 1 1.1zM10.1 204h257.3l-258.3 1.1zM267.4 10.2l1 194.9-1-1.1zM268.4 9.2v195.9l-1-194.9z"/>
</g>
<path d="M219.8 180.2h4.8M233.3 180.2h3.5" fill="none" stroke="#000" stroke-width=".2"/>
<path d="M251.9 177v3.2" fill="none" stroke="#000" stroke-width=".21"/>
</svg>
